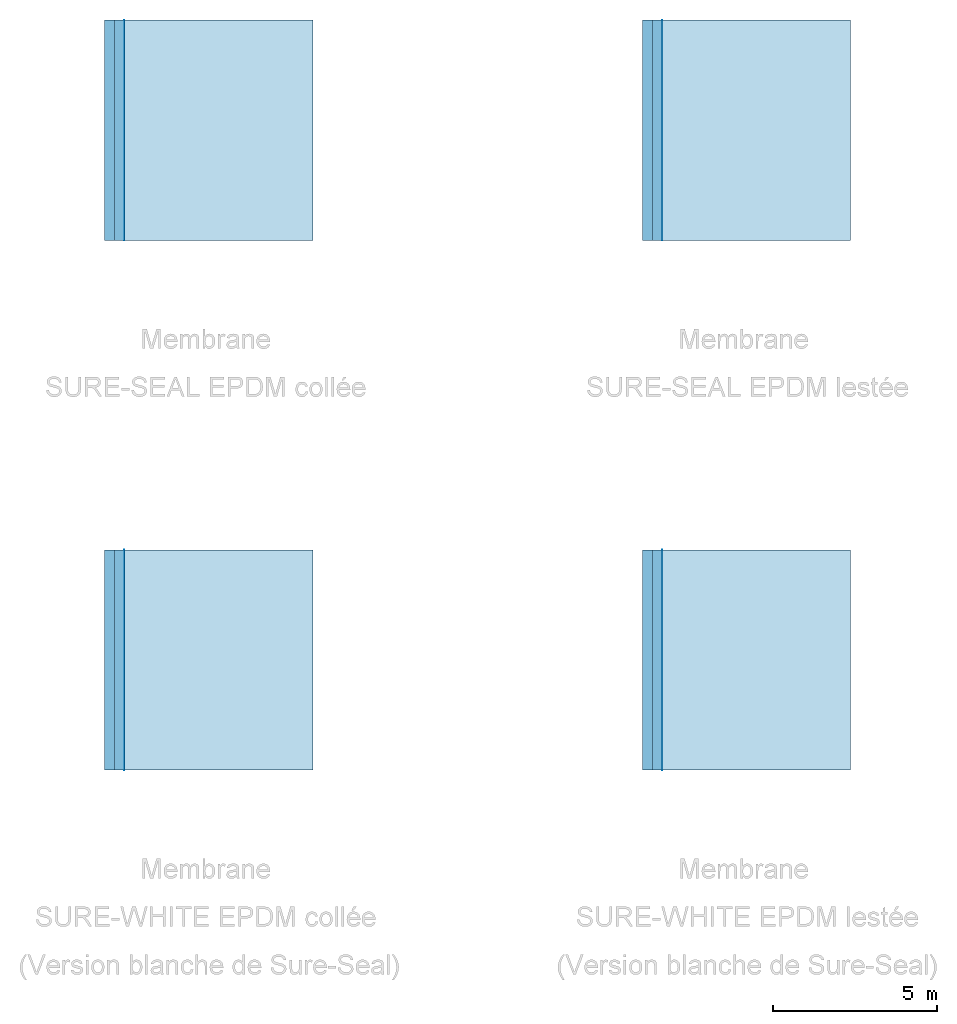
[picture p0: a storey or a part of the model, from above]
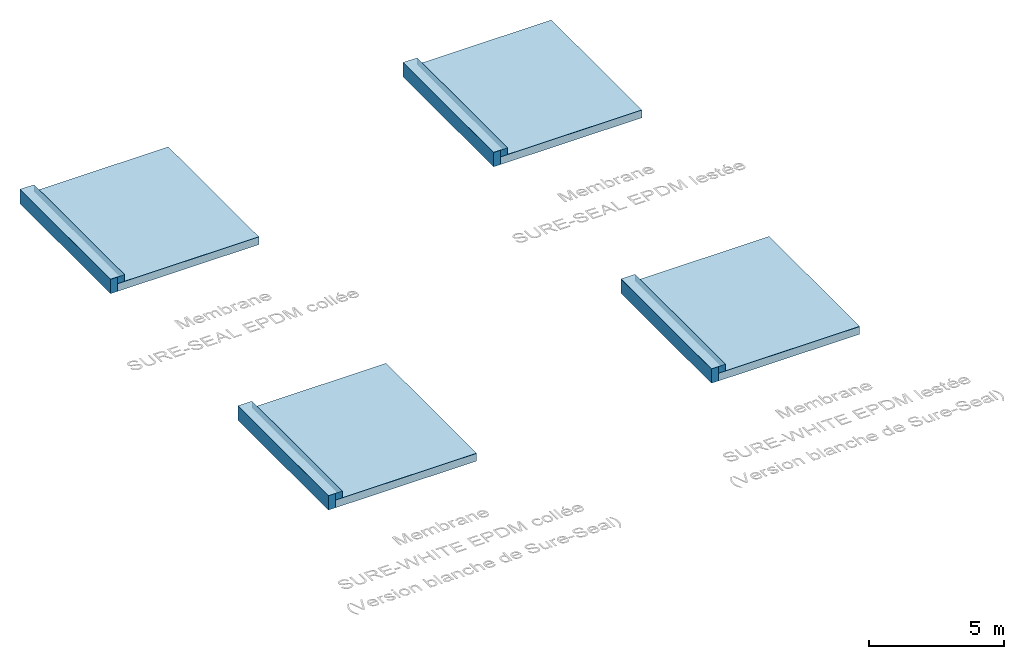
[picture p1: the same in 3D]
Properties of the parts of a building model (IFC2X3)

# File
Description: ViewDefinition [CoordinationView_V2.0], RevitIdentifiers [ContentGUID: ba8bcfdc-dbaa-49fa-ac56-a6aa088a99af, VersionGUID: 5cfe74cc-807a-4382-9c4a-9021d2856630, NumberOfSaves: 82], CoordinateReference [CoordinateBase: Coordonnées partagées]
File name: FR_Toit_VMBSO_SURE-SEAL_SURE-WHITE_EPDM_Rvt2025.ifc
Time: 2025-10-31T11:01:40+01:00
Written by: ODA SDAI 24.12
Made in: Autodesk Revit 25.3.0.46 (FRA) - IFC 25.3.0.46

# IfcSite, Default
RefLatitude: 42, 24, 53, 508911; RefLongitude: -71, -15, -29, -58837; RefElevation: 0 mm

# IfcBuilding
Pset_BuildingCommon - NumberOfStoreys: 1

# IfcBuildingStorey: Niveau:Niveau 1, Niveau 1
LongName: Niveau 1; Elevation: 0 mm

# IfcBuildingElementProxy: Texte 3D:Model Text 1 (4)
In: Niveau 1
Pset_BuildingElementProxyCommon - Reference: Model Text 1; sets with these values: 2
Name (Texte 3D:Model Text 1:...)
24701
24706
37521
37522

# IfcRoof: Toit de base:Membrane Sure-Seal EPDM Partie courante collée, Toit de base:Membrane Sure-Seal EPDM Partie courante collée:25614
In: Niveau 1
Material: Membrane Sure-Seal EPDM collée_Partie courante 1.2 mm, Colle de contact Spray fix ou Bonding adhesive 1.1 mm
Pset_QuantityTakeOff - Reference: Membrane Sure-Seal EPDM Partie courante collée
Pset_RoofCommon - Reference: Membrane Sure-Seal EPDM Partie courante collée; IsExternal: yes; ProjectedArea: 38.5877 m2; TotalArea: 38.5877 m2

# IfcRoof: Toit de base:Membrane Sure-Seal EPDM Partie courante lestée, Toit de base:Membrane Sure-Seal EPDM Partie courante lestée:26349
In: Niveau 1
Material: Film de protection polyester 0.8 mm, Membrane Sure-Seal EPDM lestée_Partie courante 1.5 mm
Pset_QuantityTakeOff - Reference: Membrane Sure-Seal EPDM Partie courante lestée
Pset_RoofCommon - IsExternal: yes; Reference: Membrane Sure-Seal EPDM Partie courante lestée; ProjectedArea: 38.5877 m2; TotalArea: 38.5877 m2

# IfcRoof: Toit de base:Membrane Sure-Seal EPDM_Acrotère (2)
In: Niveau 1
Material: Membrane Sure-Seal EPDM collée_Acrotère/Relevé 1.5 mm, Colle de contact Spray fix ou Bonding adhesive 1.1 mm
Pset_ManufacturerTypeInformation - Manufacturer: VM BUILDING SOLUTIONS
Pset_QuantityTakeOff - Reference: Membrane Sure-Seal EPDM_Acrotère
Pset_RoofCommon - IsExternal: yes; Reference: Membrane Sure-Seal EPDM_Acrotère; ProjectedArea: 4.05083 m2; TotalArea: 4.05083 m2
Name (Toit de base:Membrane Sure-Seal EPDM_Acrotère:...)
31611
32271

# IfcRoof: Toit de base:Membrane Sure-White EPDM Partie courante collée, Toit de base:Membrane Sure-White EPDM Partie courante collée:37530
In: Niveau 1
Material: Membrane Sure-White EPDM collée_Partie courante 1.5 mm, Colle de contact Spray fix ou Bonding adhesive 1.1 mm
Pset_QuantityTakeOff - Reference: Membrane Sure-White EPDM Partie courante collée
Pset_RoofCommon - IsExternal: yes; Reference: Membrane Sure-White EPDM Partie courante collée; ProjectedArea: 38.5877 m2; TotalArea: 38.5877 m2

# IfcRoof: Toit de base:Membrane Sure-White EPDM Partie courante lestée, Toit de base:Membrane Sure-White EPDM Partie courante lestée:37570
In: Niveau 1
Material: Film de protection polyester 0.8 mm, Membrane Sure-White EPDM lestée_Partie courante 1.5 mm
Pset_QuantityTakeOff - Reference: Membrane Sure-White EPDM Partie courante lestée
Pset_RoofCommon - IsExternal: yes; Reference: Membrane Sure-White EPDM Partie courante lestée; ProjectedArea: 38.5877 m2; TotalArea: 38.5877 m2

# IfcRoof: Toit de base:Membrane Sure-White EPDM_Acrotère (2)
In: Niveau 1
Material: Membrane Sure-White EPDM collée_Acrotère/Relevé 1.5 mm, Colle de contact Spray fix ou Bonding adhesive 1.1 mm
Pset_ManufacturerTypeInformation - Manufacturer: VM BUILDING SOLUTIONS
Pset_QuantityTakeOff - Reference: Membrane Sure-White EPDM_Acrotère
Pset_RoofCommon - IsExternal: yes; Reference: Membrane Sure-White EPDM_Acrotère; ProjectedArea: 4.05083 m2; TotalArea: 4.05083 m2
Name (Toit de base:Membrane Sure-White EPDM_Acrotère:...)
37611
37639

# IfcRoof: Toit de base:Toit-Support autorisé (4)
In: Niveau 1
Material: Isolation 100 mm, Pare vapeur 0.8 mm, Béton de pente 50 mm, Structure porteuse 200 mm
Pset_QuantityTakeOff - Reference: Toit-Support autorisé
Pset_RoofCommon - IsExternal: yes; Reference: Toit-Support autorisé; ProjectedArea: 40.602 m2; TotalArea: 40.602 m2
Name (Toit de base:Toit-Support autorisé:...)
31936
32010
37621
37630

# IfcSlab: Toit de base:Membrane Sure-Seal EPDM Partie courante collée, Toit de base:Membrane Sure-Seal EPDM Partie courante collée:25614
In: Niveau 1
PredefinedType: ROOF; Material: Membrane Sure-Seal EPDM collée_Partie courante 1.2 mm, Colle de contact Spray fix ou Bonding adhesive 1.1 mm
Pset_QuantityTakeOff - Reference: Membrane Sure-Seal EPDM Partie courante collée; sets with these values: 2
Pset_SlabCommon - Reference: Membrane Sure-Seal EPDM Partie courante collée; IsExternal: yes; PitchAngle: 0 deg

# IfcSlab: Toit de base:Membrane Sure-Seal EPDM Partie courante lestée, Toit de base:Membrane Sure-Seal EPDM Partie courante lestée:26349
In: Niveau 1
PredefinedType: ROOF; Material: Film de protection polyester 0.8 mm, Membrane Sure-Seal EPDM lestée_Partie courante 1.5 mm
Pset_QuantityTakeOff - Reference: Membrane Sure-Seal EPDM Partie courante lestée; sets with these values: 2
Pset_SlabCommon - IsExternal: yes; PitchAngle: 0 deg; Reference: Membrane Sure-Seal EPDM Partie courante lestée

# IfcSlab: Toit de base:Membrane Sure-Seal EPDM_Acrotère (2)
In: Niveau 1
PredefinedType: ROOF; Material: Membrane Sure-Seal EPDM collée_Acrotère/Relevé 1.5 mm, Colle de contact Spray fix ou Bonding adhesive 1.1 mm
Pset_QuantityTakeOff - Reference: Membrane Sure-Seal EPDM_Acrotère; sets with these values: 2
Pset_SlabCommon - IsExternal: yes; PitchAngle: 0 deg; Reference: Membrane Sure-Seal EPDM_Acrotère
Name (Toit de base:Membrane Sure-Seal EPDM_Acrotère:...)
31611
32271

# IfcSlab: Toit de base:Membrane Sure-White EPDM Partie courante collée, Toit de base:Membrane Sure-White EPDM Partie courante collée:37530
In: Niveau 1
PredefinedType: ROOF; Material: Membrane Sure-White EPDM collée_Partie courante 1.5 mm, Colle de contact Spray fix ou Bonding adhesive 1.1 mm
Pset_QuantityTakeOff - Reference: Membrane Sure-White EPDM Partie courante collée; sets with these values: 2
Pset_SlabCommon - IsExternal: yes; PitchAngle: 0 deg; Reference: Membrane Sure-White EPDM Partie courante collée

# IfcSlab: Toit de base:Membrane Sure-White EPDM Partie courante lestée, Toit de base:Membrane Sure-White EPDM Partie courante lestée:37570
In: Niveau 1
PredefinedType: ROOF; Material: Film de protection polyester 0.8 mm, Membrane Sure-White EPDM lestée_Partie courante 1.5 mm
Pset_QuantityTakeOff - Reference: Membrane Sure-White EPDM Partie courante lestée; sets with these values: 2
Pset_SlabCommon - IsExternal: yes; PitchAngle: 0 deg; Reference: Membrane Sure-White EPDM Partie courante lestée

# IfcSlab: Toit de base:Membrane Sure-White EPDM_Acrotère (2)
In: Niveau 1
PredefinedType: ROOF; Material: Membrane Sure-White EPDM collée_Acrotère/Relevé 1.5 mm, Colle de contact Spray fix ou Bonding adhesive 1.1 mm
Pset_QuantityTakeOff - Reference: Membrane Sure-White EPDM_Acrotère; sets with these values: 2
Pset_SlabCommon - IsExternal: yes; PitchAngle: 0 deg; Reference: Membrane Sure-White EPDM_Acrotère
Name (Toit de base:Membrane Sure-White EPDM_Acrotère:...)
37611
37639

# IfcSlab: Toit de base:Toit-Support autorisé (4)
In: Niveau 1
PredefinedType: ROOF; Material: Isolation 100 mm, Pare vapeur 0.8 mm, Béton de pente 50 mm, Structure porteuse 200 mm
Pset_QuantityTakeOff - Reference: Toit-Support autorisé; sets with these values: 2
Pset_SlabCommon - IsExternal: yes; PitchAngle: 0 deg; Reference: Toit-Support autorisé
Name (Toit de base:Toit-Support autorisé:...)
31936
32010
37621
37630

# IfcWallStandardCase: Mur de base:Membrane Sure-Seal EPDM Relevé collé (2)
In: Niveau 1
Type - PredefinedType: STANDARD; Material: Membrane Sure-Seal EPDM collée_Acrotère/Relevé 1.2 mm, Colle de contact Spray fix ou Bonding adhesive 1.1 mm
Type - Pset_ReinforcementBarPitchOfWall - Description: Avec l'EPDM Sure-Seal, les toitures ont une durée de vie extrêmement longue de 70 ans et plus. Sure-Seal est 100 % recyclable, très respectueux de l'environnement, possède un certificat d'étanchéité à l'eau de pluie et l'approbation ATG-UEAtc. Elle protège le toit des conditions météorologiques extrêmes.
Pset_QuantityTakeOff - Reference: Membrane Sure-Seal EPDM Relevé collé; sets with these values: 2
Pset_WallCommon - IsExternal: yes; ExtendToStructure: no; LoadBearing: no; Reference: Membrane Sure-Seal EPDM Relevé collé
Name (Mur de base:Membrane Sure-Seal EPDM Relevé collé:...)
25628
26363

# IfcWallStandardCase: Mur de base:Membrane Sure-White EPDM collée-Relevé (2)
In: Niveau 1
Type - PredefinedType: STANDARD; Material: Membrane Sure-White EPDM collée_Acrotère/Relevé 1.5 mm, Colle de contact Spray fix ou Bonding adhesive 1.1 mm
Type - Pset_ReinforcementBarPitchOfWall - Description: Outre l’EPDM noir Sure-Seal, il existe également Sure-White, une variante blanche qui réfléchit au maximum le rayonnement solaire, ce qui permet de réaliser des économies d’énergie et d’assurer un climat intérieur plus confortable
Pset_QuantityTakeOff - Reference: Membrane Sure-White EPDM collée-Relevé; sets with these values: 2
Pset_WallCommon - IsExternal: yes; ExtendToStructure: no; LoadBearing: no; Reference: Membrane Sure-White EPDM collée-Relevé
Name (Mur de base:Membrane Sure-White EPDM collée-Relevé:...)
37537
37577

# IfcWallStandardCase: Mur de base:Mur 1 (8)
In: Niveau 1
Type - PredefinedType: STANDARD; Material: Isolation 100 mm, Maçonnerie ascendante 200 mm
Pset_QuantityTakeOff - Reference: Mur 1; sets with these values: 2
Pset_WallCommon - IsExternal: yes; Reference: Mur 1; ExtendToStructure: no; LoadBearing: no
Name (Mur de base:Mur 1:...)
25626
25627
26361
26362
37535
37536
37575
37576
